VERSION 5.7 ;
  NOWIREEXTENSIONATPIN ON ;
  DIVIDERCHAR "/" ;
  BUSBITCHARS "[]" ;
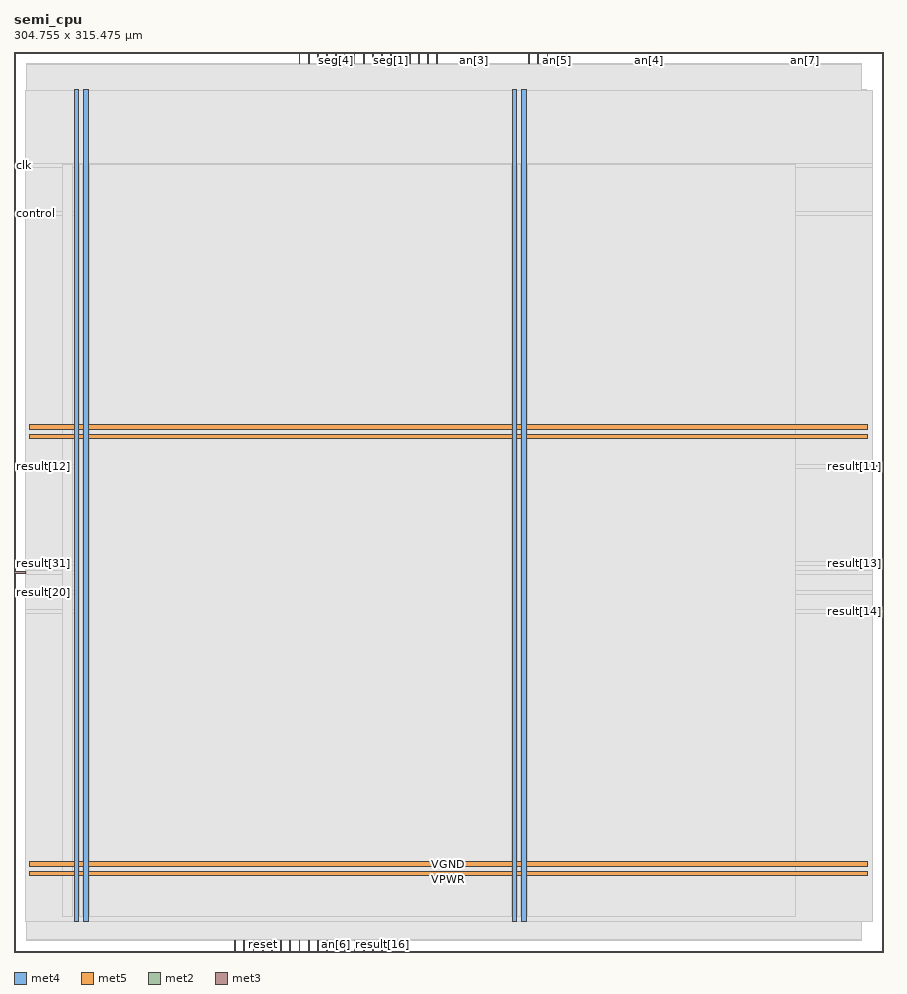
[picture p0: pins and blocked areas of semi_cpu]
MACRO semi_cpu
  CLASS BLOCK ;
  FOREIGN semi_cpu ;
  ORIGIN 0.000 0.000 ;
  SIZE 304.755 BY 315.475 ;
  PIN VGND
    DIRECTION INOUT ;
    USE GROUND ;
    PORT
      LAYER met4 ;
        RECT 24.340 10.640 25.940 302.160 ;
    END
    PORT
      LAYER met4 ;
        RECT 177.940 10.640 179.540 302.160 ;
    END
    PORT
      LAYER met5 ;
        RECT 5.280 30.030 299.240 31.630 ;
    END
    PORT
      LAYER met5 ;
        RECT 5.280 183.210 299.240 184.810 ;
    END
  END VGND
  PIN VPWR
    DIRECTION INOUT ;
    USE POWER ;
    PORT
      LAYER met4 ;
        RECT 21.040 10.640 22.640 302.160 ;
    END
    PORT
      LAYER met4 ;
        RECT 174.640 10.640 176.240 302.160 ;
    END
    PORT
      LAYER met5 ;
        RECT 5.280 26.730 299.240 28.330 ;
    END
    PORT
      LAYER met5 ;
        RECT 5.280 179.910 299.240 181.510 ;
    END
  END VPWR
  PIN an[0]
    DIRECTION OUTPUT ;
    USE SIGNAL ;
    ANTENNADIFFAREA 0.795200 ;
    PORT
      LAYER met2 ;
        RECT 141.770 311.475 142.050 315.475 ;
    END
  END an[0]
  PIN an[1]
    DIRECTION OUTPUT ;
    USE SIGNAL ;
    ANTENNADIFFAREA 0.795200 ;
    PORT
      LAYER met2 ;
        RECT 138.550 311.475 138.830 315.475 ;
    END
  END an[1]
  PIN an[2]
    DIRECTION OUTPUT ;
    USE SIGNAL ;
    ANTENNADIFFAREA 0.445500 ;
    PORT
      LAYER met2 ;
        RECT 116.010 0.000 116.290 4.000 ;
    END
  END an[2]
  PIN an[3]
    DIRECTION OUTPUT ;
    USE SIGNAL ;
    ANTENNADIFFAREA 0.795200 ;
    PORT
      LAYER met2 ;
        RECT 161.090 311.475 161.370 315.475 ;
    END
  END an[3]
  PIN an[4]
    DIRECTION OUTPUT ;
    USE SIGNAL ;
    ANTENNADIFFAREA 0.795200 ;
    PORT
      LAYER met2 ;
        RECT 222.270 311.475 222.550 315.475 ;
    END
  END an[4]
  PIN an[5]
    DIRECTION OUTPUT ;
    USE SIGNAL ;
    ANTENNADIFFAREA 0.795200 ;
    PORT
      LAYER met2 ;
        RECT 190.070 311.475 190.350 315.475 ;
    END
  END an[5]
  PIN an[6]
    DIRECTION OUTPUT ;
    USE SIGNAL ;
    ANTENNADIFFAREA 0.445500 ;
    PORT
      LAYER met2 ;
        RECT 112.790 0.000 113.070 4.000 ;
    END
  END an[6]
  PIN an[7]
    DIRECTION OUTPUT ;
    USE SIGNAL ;
    ANTENNADIFFAREA 0.795200 ;
    PORT
      LAYER met2 ;
        RECT 277.010 311.475 277.290 315.475 ;
    END
  END an[7]
  PIN clk
    DIRECTION INPUT ;
    USE SIGNAL ;
    ANTENNAGATEAREA 0.852000 ;
    PORT
      LAYER met3 ;
        RECT 0.000 275.440 4.000 276.040 ;
    END
  END clk
  PIN control
    DIRECTION INPUT ;
    USE SIGNAL ;
    ANTENNAGATEAREA 0.126000 ;
    PORT
      LAYER met3 ;
        RECT 0.000 258.440 4.000 259.040 ;
    END
  END control
  PIN reset
    DIRECTION INPUT ;
    USE SIGNAL ;
    ANTENNAGATEAREA 0.247500 ;
    ANTENNADIFFAREA 0.434700 ;
    PORT
      LAYER met2 ;
        RECT 87.030 0.000 87.310 4.000 ;
    END
  END reset
  PIN result[0]
    DIRECTION OUTPUT ;
    USE SIGNAL ;
    ANTENNADIFFAREA 0.795200 ;
    PORT
      LAYER met2 ;
        RECT 106.350 311.475 106.630 315.475 ;
    END
  END result[0]
  PIN result[10]
    DIRECTION OUTPUT ;
    USE SIGNAL ;
    ANTENNADIFFAREA 0.795200 ;
    PORT
      LAYER met2 ;
        RECT 193.290 311.475 193.570 315.475 ;
    END
  END result[10]
  PIN result[11]
    DIRECTION OUTPUT ;
    USE SIGNAL ;
    ANTENNADIFFAREA 0.445500 ;
    PORT
      LAYER met3 ;
        RECT 300.755 170.040 304.755 170.640 ;
    END
  END result[11]
  PIN result[12]
    DIRECTION OUTPUT ;
    USE SIGNAL ;
    ANTENNADIFFAREA 0.445500 ;
    PORT
      LAYER met3 ;
        RECT 0.000 170.040 4.000 170.640 ;
    END
  END result[12]
  PIN result[13]
    DIRECTION OUTPUT ;
    USE SIGNAL ;
    ANTENNADIFFAREA 0.445500 ;
    PORT
      LAYER met3 ;
        RECT 300.755 136.040 304.755 136.640 ;
    END
  END result[13]
  PIN result[14]
    DIRECTION OUTPUT ;
    USE SIGNAL ;
    ANTENNADIFFAREA 0.445500 ;
    PORT
      LAYER met3 ;
        RECT 300.755 119.040 304.755 119.640 ;
    END
  END result[14]
  PIN result[15]
    DIRECTION OUTPUT ;
    USE SIGNAL ;
    ANTENNADIFFAREA 0.445500 ;
    PORT
      LAYER met2 ;
        RECT 119.230 0.000 119.510 4.000 ;
    END
  END result[15]
  PIN result[16]
    DIRECTION OUTPUT ;
    USE SIGNAL ;
    ANTENNADIFFAREA 0.445500 ;
    PORT
      LAYER met2 ;
        RECT 128.890 0.000 129.170 4.000 ;
    END
  END result[16]
  PIN result[17]
    DIRECTION OUTPUT ;
    USE SIGNAL ;
    ANTENNADIFFAREA 0.445500 ;
    PORT
      LAYER met2 ;
        RECT 122.450 0.000 122.730 4.000 ;
    END
  END result[17]
  PIN result[18]
    DIRECTION OUTPUT ;
    USE SIGNAL ;
    ANTENNADIFFAREA 0.445500 ;
    PORT
      LAYER met2 ;
        RECT 125.670 0.000 125.950 4.000 ;
    END
  END result[18]
  PIN result[19]
    DIRECTION OUTPUT ;
    USE SIGNAL ;
    ANTENNADIFFAREA 0.445500 ;
    PORT
      LAYER met2 ;
        RECT 103.130 0.000 103.410 4.000 ;
    END
  END result[19]
  PIN result[1]
    DIRECTION OUTPUT ;
    USE SIGNAL ;
    ANTENNADIFFAREA 0.795200 ;
    PORT
      LAYER met2 ;
        RECT 99.910 311.475 100.190 315.475 ;
    END
  END result[1]
  PIN result[20]
    DIRECTION OUTPUT ;
    USE SIGNAL ;
    ANTENNADIFFAREA 0.445500 ;
    PORT
      LAYER met3 ;
        RECT 0.000 125.840 4.000 126.440 ;
    END
  END result[20]
  PIN result[21]
    DIRECTION OUTPUT ;
    USE SIGNAL ;
    ANTENNADIFFAREA 0.445500 ;
    PORT
      LAYER met2 ;
        RECT 83.810 0.000 84.090 4.000 ;
    END
  END result[21]
  PIN result[22]
    DIRECTION OUTPUT ;
    USE SIGNAL ;
    ANTENNADIFFAREA 0.445500 ;
    PORT
      LAYER met2 ;
        RECT 96.690 0.000 96.970 4.000 ;
    END
  END result[22]
  PIN result[23]
    DIRECTION OUTPUT ;
    USE SIGNAL ;
    ANTENNADIFFAREA 0.445500 ;
    PORT
      LAYER met2 ;
        RECT 77.370 0.000 77.650 4.000 ;
    END
  END result[23]
  PIN result[24]
    DIRECTION OUTPUT ;
    USE SIGNAL ;
    ANTENNADIFFAREA 0.445500 ;
    PORT
      LAYER met2 ;
        RECT 99.910 0.000 100.190 4.000 ;
    END
  END result[24]
  PIN result[25]
    DIRECTION OUTPUT ;
    USE SIGNAL ;
    ANTENNADIFFAREA 0.445500 ;
    PORT
      LAYER met2 ;
        RECT 80.590 0.000 80.870 4.000 ;
    END
  END result[25]
  PIN result[26]
    DIRECTION OUTPUT ;
    USE SIGNAL ;
    ANTENNADIFFAREA 0.445500 ;
    PORT
      LAYER met2 ;
        RECT 90.250 0.000 90.530 4.000 ;
    END
  END result[26]
  PIN result[27]
    DIRECTION OUTPUT ;
    USE SIGNAL ;
    ANTENNADIFFAREA 0.445500 ;
    PORT
      LAYER met2 ;
        RECT 93.470 0.000 93.750 4.000 ;
    END
  END result[27]
  PIN result[28]
    DIRECTION OUTPUT ;
    USE SIGNAL ;
    ANTENNADIFFAREA 0.445500 ;
    PORT
      LAYER met3 ;
        RECT 0.000 132.640 4.000 133.240 ;
    END
  END result[28]
  PIN result[29]
    DIRECTION OUTPUT ;
    USE SIGNAL ;
    ANTENNADIFFAREA 0.445500 ;
    PORT
      LAYER met2 ;
        RECT 109.570 0.000 109.850 4.000 ;
    END
  END result[29]
  PIN result[2]
    DIRECTION OUTPUT ;
    USE SIGNAL ;
    ANTENNADIFFAREA 0.795200 ;
    PORT
      LAYER met2 ;
        RECT 103.130 311.475 103.410 315.475 ;
    END
  END result[2]
  PIN result[30]
    DIRECTION OUTPUT ;
    USE SIGNAL ;
    ANTENNADIFFAREA 0.445500 ;
    PORT
      LAYER met2 ;
        RECT 106.350 0.000 106.630 4.000 ;
    END
  END result[30]
  PIN result[31]
    DIRECTION OUTPUT ;
    USE SIGNAL ;
    ANTENNADIFFAREA 0.445500 ;
    PORT
      LAYER met3 ;
        RECT 0.000 136.040 4.000 136.640 ;
    END
  END result[31]
  PIN result[3]
    DIRECTION OUTPUT ;
    USE SIGNAL ;
    ANTENNADIFFAREA 0.795200 ;
    PORT
      LAYER met2 ;
        RECT 109.570 311.475 109.850 315.475 ;
    END
  END result[3]
  PIN result[4]
    DIRECTION OUTPUT ;
    USE SIGNAL ;
    ANTENNADIFFAREA 0.795200 ;
    PORT
      LAYER met2 ;
        RECT 135.330 311.475 135.610 315.475 ;
    END
  END result[4]
  PIN result[5]
    DIRECTION OUTPUT ;
    USE SIGNAL ;
    ANTENNADIFFAREA 0.795200 ;
    PORT
      LAYER met2 ;
        RECT 144.990 311.475 145.270 315.475 ;
    END
  END result[5]
  PIN result[6]
    DIRECTION OUTPUT ;
    USE SIGNAL ;
    ANTENNADIFFAREA 0.795200 ;
    PORT
      LAYER met2 ;
        RECT 148.210 311.475 148.490 315.475 ;
    END
  END result[6]
  PIN result[7]
    DIRECTION OUTPUT ;
    USE SIGNAL ;
    ANTENNADIFFAREA 0.795200 ;
    PORT
      LAYER met2 ;
        RECT 183.630 311.475 183.910 315.475 ;
    END
  END result[7]
  PIN result[8]
    DIRECTION OUTPUT ;
    USE SIGNAL ;
    ANTENNADIFFAREA 0.795200 ;
    PORT
      LAYER met2 ;
        RECT 186.850 311.475 187.130 315.475 ;
    END
  END result[8]
  PIN result[9]
    DIRECTION OUTPUT ;
    USE SIGNAL ;
    ANTENNADIFFAREA 0.795200 ;
    PORT
      LAYER met2 ;
        RECT 180.410 311.475 180.690 315.475 ;
    END
  END result[9]
  PIN seg[0]
    DIRECTION OUTPUT ;
    USE SIGNAL ;
    ANTENNADIFFAREA 0.795200 ;
    PORT
      LAYER met2 ;
        RECT 122.450 311.475 122.730 315.475 ;
    END
  END seg[0]
  PIN seg[1]
    DIRECTION OUTPUT ;
    USE SIGNAL ;
    ANTENNADIFFAREA 1.336500 ;
    PORT
      LAYER met2 ;
        RECT 132.110 311.475 132.390 315.475 ;
    END
  END seg[1]
  PIN seg[2]
    DIRECTION OUTPUT ;
    USE SIGNAL ;
    ANTENNADIFFAREA 0.795200 ;
    PORT
      LAYER met2 ;
        RECT 128.890 311.475 129.170 315.475 ;
    END
  END seg[2]
  PIN seg[3]
    DIRECTION OUTPUT ;
    USE SIGNAL ;
    ANTENNADIFFAREA 0.795200 ;
    PORT
      LAYER met2 ;
        RECT 116.010 311.475 116.290 315.475 ;
    END
  END seg[3]
  PIN seg[4]
    DIRECTION OUTPUT ;
    USE SIGNAL ;
    ANTENNADIFFAREA 0.795200 ;
    PORT
      LAYER met2 ;
        RECT 112.790 311.475 113.070 315.475 ;
    END
  END seg[4]
  PIN seg[5]
    DIRECTION OUTPUT ;
    USE SIGNAL ;
    ANTENNADIFFAREA 0.891000 ;
    PORT
      LAYER met2 ;
        RECT 125.670 311.475 125.950 315.475 ;
    END
  END seg[5]
  PIN seg[6]
    DIRECTION OUTPUT ;
    USE SIGNAL ;
    ANTENNADIFFAREA 0.795200 ;
    PORT
      LAYER met2 ;
        RECT 119.230 311.475 119.510 315.475 ;
    END
  END seg[6]
  OBS
      LAYER nwell ;
        RECT 5.330 10.795 299.190 302.110 ;
      LAYER li1 ;
        RECT 5.520 10.795 299.000 302.005 ;
      LAYER met1 ;
        RECT 4.210 10.640 299.000 302.160 ;
      LAYER met2 ;
        RECT 4.230 311.195 99.630 311.475 ;
        RECT 100.470 311.195 102.850 311.475 ;
        RECT 103.690 311.195 106.070 311.475 ;
        RECT 106.910 311.195 109.290 311.475 ;
        RECT 110.130 311.195 112.510 311.475 ;
        RECT 113.350 311.195 115.730 311.475 ;
        RECT 116.570 311.195 118.950 311.475 ;
        RECT 119.790 311.195 122.170 311.475 ;
        RECT 123.010 311.195 125.390 311.475 ;
        RECT 126.230 311.195 128.610 311.475 ;
        RECT 129.450 311.195 131.830 311.475 ;
        RECT 132.670 311.195 135.050 311.475 ;
        RECT 135.890 311.195 138.270 311.475 ;
        RECT 139.110 311.195 141.490 311.475 ;
        RECT 142.330 311.195 144.710 311.475 ;
        RECT 145.550 311.195 147.930 311.475 ;
        RECT 148.770 311.195 160.810 311.475 ;
        RECT 161.650 311.195 180.130 311.475 ;
        RECT 180.970 311.195 183.350 311.475 ;
        RECT 184.190 311.195 186.570 311.475 ;
        RECT 187.410 311.195 189.790 311.475 ;
        RECT 190.630 311.195 193.010 311.475 ;
        RECT 193.850 311.195 221.990 311.475 ;
        RECT 222.830 311.195 276.730 311.475 ;
        RECT 277.570 311.195 297.070 311.475 ;
        RECT 4.230 4.280 297.070 311.195 ;
        RECT 4.230 4.000 77.090 4.280 ;
        RECT 77.930 4.000 80.310 4.280 ;
        RECT 81.150 4.000 83.530 4.280 ;
        RECT 84.370 4.000 86.750 4.280 ;
        RECT 87.590 4.000 89.970 4.280 ;
        RECT 90.810 4.000 93.190 4.280 ;
        RECT 94.030 4.000 96.410 4.280 ;
        RECT 97.250 4.000 99.630 4.280 ;
        RECT 100.470 4.000 102.850 4.280 ;
        RECT 103.690 4.000 106.070 4.280 ;
        RECT 106.910 4.000 109.290 4.280 ;
        RECT 110.130 4.000 112.510 4.280 ;
        RECT 113.350 4.000 115.730 4.280 ;
        RECT 116.570 4.000 118.950 4.280 ;
        RECT 119.790 4.000 122.170 4.280 ;
        RECT 123.010 4.000 125.390 4.280 ;
        RECT 126.230 4.000 128.610 4.280 ;
        RECT 129.450 4.000 297.070 4.280 ;
      LAYER met3 ;
        RECT 3.990 276.440 300.755 302.085 ;
        RECT 4.400 275.040 300.755 276.440 ;
        RECT 3.990 259.440 300.755 275.040 ;
        RECT 4.400 258.040 300.755 259.440 ;
        RECT 3.990 171.040 300.755 258.040 ;
        RECT 4.400 169.640 300.355 171.040 ;
        RECT 3.990 137.040 300.755 169.640 ;
        RECT 4.400 135.640 300.355 137.040 ;
        RECT 3.990 133.640 300.755 135.640 ;
        RECT 4.400 132.240 300.755 133.640 ;
        RECT 3.990 126.840 300.755 132.240 ;
        RECT 4.400 125.440 300.755 126.840 ;
        RECT 3.990 120.040 300.755 125.440 ;
        RECT 3.990 118.640 300.355 120.040 ;
        RECT 3.990 10.715 300.755 118.640 ;
      LAYER met4 ;
        RECT 16.855 12.415 20.640 275.905 ;
        RECT 23.040 12.415 23.940 275.905 ;
        RECT 26.340 12.415 174.240 275.905 ;
        RECT 176.640 12.415 177.540 275.905 ;
        RECT 179.940 12.415 273.865 275.905 ;
  END
END semi_cpu
END LIBRARY

